One B-rep face of a CAD part: STEP entity #39522.
In plain terms, the planar face has unit normal (0, 0, 1).
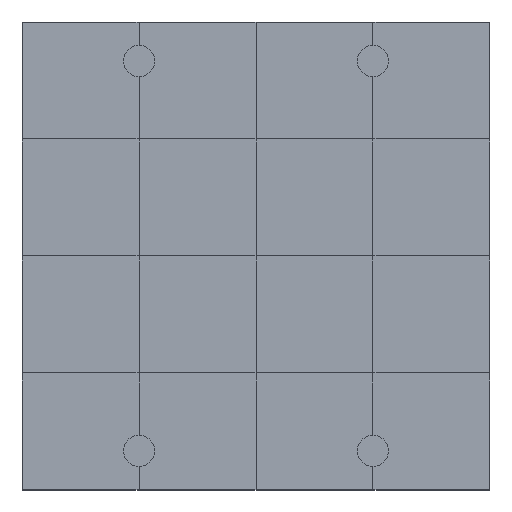
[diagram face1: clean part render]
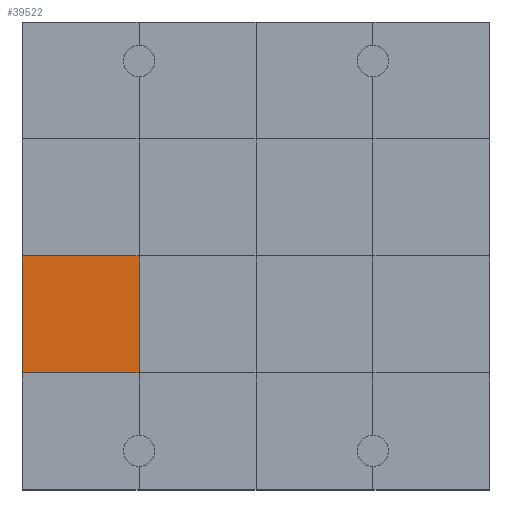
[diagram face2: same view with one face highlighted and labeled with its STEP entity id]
Its self-contained STEP definition (entity closure, numbers rounded to 3 decimals):
#39072 = VERTEX_POINT('',#39073);
#39073 = CARTESIAN_POINT('',(0.,3.,1.2));
#39087 = PLANE('',#39088);
#39088 = AXIS2_PLACEMENT_3D('',#39089,#39090,#39091);
#39089 = CARTESIAN_POINT('',(0.,3.,0.));
#39090 = DIRECTION('',(1.,0.,-0.));
#39091 = DIRECTION('',(0.,0.,1.));
#39113 = PLANE('',#39114);
#39114 = AXIS2_PLACEMENT_3D('',#39115,#39116,#39117);
#39115 = CARTESIAN_POINT('',(0.,0.,1.2));
#39116 = DIRECTION('',(0.,0.,1.));
#39117 = DIRECTION('',(1.,0.,-0.));
#39264 = VERTEX_POINT('',#39265);
#39265 = CARTESIAN_POINT('',(3.,3.,1.2));
#39286 = EDGE_CURVE('',#39072,#39264,#39287,.T.);
#39287 = SURFACE_CURVE('',#39288,(#39292,#39299),.PCURVE_S1.);
#39288 = LINE('',#39289,#39290);
#39289 = CARTESIAN_POINT('',(0.,3.,1.2));
#39290 = VECTOR('',#39291,1.);
#39291 = DIRECTION('',(1.,0.,-0.));
#39292 = PCURVE('',#39113,#39293);
#39293 = DEFINITIONAL_REPRESENTATION('',(#39294),#39298);
#39294 = LINE('',#39295,#39296);
#39295 = CARTESIAN_POINT('',(0.,3.));
#39296 = VECTOR('',#39297,1.);
#39297 = DIRECTION('',(1.,0.));
#39298 = ( GEOMETRIC_REPRESENTATION_CONTEXT(2) 
PARAMETRIC_REPRESENTATION_CONTEXT() REPRESENTATION_CONTEXT('2D SPACE',''
  ) );
#39299 = PCURVE('',#39300,#39305);
#39300 = PLANE('',#39301);
#39301 = AXIS2_PLACEMENT_3D('',#39302,#39303,#39304);
#39302 = CARTESIAN_POINT('',(0.,3.,1.2));
#39303 = DIRECTION('',(0.,0.,1.));
#39304 = DIRECTION('',(1.,0.,-0.));
#39305 = DEFINITIONAL_REPRESENTATION('',(#39306),#39310);
#39306 = LINE('',#39307,#39308);
#39307 = CARTESIAN_POINT('',(0.,0.));
#39308 = VECTOR('',#39309,1.);
#39309 = DIRECTION('',(1.,0.));
#39310 = ( GEOMETRIC_REPRESENTATION_CONTEXT(2) 
PARAMETRIC_REPRESENTATION_CONTEXT() REPRESENTATION_CONTEXT('2D SPACE',''
  ) );
#39345 = VERTEX_POINT('',#39346);
#39346 = CARTESIAN_POINT('',(0.,6.,1.2));
#39372 = EDGE_CURVE('',#39072,#39345,#39373,.T.);
#39373 = SURFACE_CURVE('',#39374,(#39378,#39385),.PCURVE_S1.);
#39374 = LINE('',#39375,#39376);
#39375 = CARTESIAN_POINT('',(0.,3.,1.2));
#39376 = VECTOR('',#39377,1.);
#39377 = DIRECTION('',(-0.,1.,0.));
#39378 = PCURVE('',#39087,#39379);
#39379 = DEFINITIONAL_REPRESENTATION('',(#39380),#39384);
#39380 = LINE('',#39381,#39382);
#39381 = CARTESIAN_POINT('',(1.2,0.));
#39382 = VECTOR('',#39383,1.);
#39383 = DIRECTION('',(0.,-1.));
#39384 = ( GEOMETRIC_REPRESENTATION_CONTEXT(2) 
PARAMETRIC_REPRESENTATION_CONTEXT() REPRESENTATION_CONTEXT('2D SPACE',''
  ) );
#39385 = PCURVE('',#39300,#39386);
#39386 = DEFINITIONAL_REPRESENTATION('',(#39387),#39391);
#39387 = LINE('',#39388,#39389);
#39388 = CARTESIAN_POINT('',(0.,0.));
#39389 = VECTOR('',#39390,1.);
#39390 = DIRECTION('',(0.,1.));
#39391 = ( GEOMETRIC_REPRESENTATION_CONTEXT(2) 
PARAMETRIC_REPRESENTATION_CONTEXT() REPRESENTATION_CONTEXT('2D SPACE',''
  ) );
#39522 = ADVANCED_FACE('',(#39523),#39300,.T.);
#39523 = FACE_BOUND('',#39524,.T.);
#39524 = EDGE_LOOP('',(#39525,#39526,#39527,#39555));
#39525 = ORIENTED_EDGE('',*,*,#39372,.F.);
#39526 = ORIENTED_EDGE('',*,*,#39286,.T.);
#39527 = ORIENTED_EDGE('',*,*,#39528,.T.);
#39528 = EDGE_CURVE('',#39264,#39529,#39531,.T.);
#39529 = VERTEX_POINT('',#39530);
#39530 = CARTESIAN_POINT('',(3.,6.,1.2));
#39531 = SURFACE_CURVE('',#39532,(#39536,#39543),.PCURVE_S1.);
#39532 = LINE('',#39533,#39534);
#39533 = CARTESIAN_POINT('',(3.,3.,1.2));
#39534 = VECTOR('',#39535,1.);
#39535 = DIRECTION('',(-0.,1.,0.));
#39536 = PCURVE('',#39300,#39537);
#39537 = DEFINITIONAL_REPRESENTATION('',(#39538),#39542);
#39538 = LINE('',#39539,#39540);
#39539 = CARTESIAN_POINT('',(3.,0.));
#39540 = VECTOR('',#39541,1.);
#39541 = DIRECTION('',(0.,1.));
#39542 = ( GEOMETRIC_REPRESENTATION_CONTEXT(2) 
PARAMETRIC_REPRESENTATION_CONTEXT() REPRESENTATION_CONTEXT('2D SPACE',''
  ) );
#39543 = PCURVE('',#39544,#39549);
#39544 = PLANE('',#39545);
#39545 = AXIS2_PLACEMENT_3D('',#39546,#39547,#39548);
#39546 = CARTESIAN_POINT('',(3.,3.,1.2));
#39547 = DIRECTION('',(0.,0.,1.));
#39548 = DIRECTION('',(1.,0.,-0.));
#39549 = DEFINITIONAL_REPRESENTATION('',(#39550),#39554);
#39550 = LINE('',#39551,#39552);
#39551 = CARTESIAN_POINT('',(0.,0.));
#39552 = VECTOR('',#39553,1.);
#39553 = DIRECTION('',(0.,1.));
#39554 = ( GEOMETRIC_REPRESENTATION_CONTEXT(2) 
PARAMETRIC_REPRESENTATION_CONTEXT() REPRESENTATION_CONTEXT('2D SPACE',''
  ) );
#39555 = ORIENTED_EDGE('',*,*,#39556,.F.);
#39556 = EDGE_CURVE('',#39345,#39529,#39557,.T.);
#39557 = SURFACE_CURVE('',#39558,(#39562,#39569),.PCURVE_S1.);
#39558 = LINE('',#39559,#39560);
#39559 = CARTESIAN_POINT('',(0.,6.,1.2));
#39560 = VECTOR('',#39561,1.);
#39561 = DIRECTION('',(1.,0.,-0.));
#39562 = PCURVE('',#39300,#39563);
#39563 = DEFINITIONAL_REPRESENTATION('',(#39564),#39568);
#39564 = LINE('',#39565,#39566);
#39565 = CARTESIAN_POINT('',(0.,3.));
#39566 = VECTOR('',#39567,1.);
#39567 = DIRECTION('',(1.,0.));
#39568 = ( GEOMETRIC_REPRESENTATION_CONTEXT(2) 
PARAMETRIC_REPRESENTATION_CONTEXT() REPRESENTATION_CONTEXT('2D SPACE',''
  ) );
#39569 = PCURVE('',#39570,#39575);
#39570 = PLANE('',#39571);
#39571 = AXIS2_PLACEMENT_3D('',#39572,#39573,#39574);
#39572 = CARTESIAN_POINT('',(0.,6.,1.2));
#39573 = DIRECTION('',(0.,0.,1.));
#39574 = DIRECTION('',(1.,0.,-0.));
#39575 = DEFINITIONAL_REPRESENTATION('',(#39576),#39580);
#39576 = LINE('',#39577,#39578);
#39577 = CARTESIAN_POINT('',(0.,0.));
#39578 = VECTOR('',#39579,1.);
#39579 = DIRECTION('',(1.,0.));
#39580 = ( GEOMETRIC_REPRESENTATION_CONTEXT(2) 
PARAMETRIC_REPRESENTATION_CONTEXT() REPRESENTATION_CONTEXT('2D SPACE',''
  ) );
